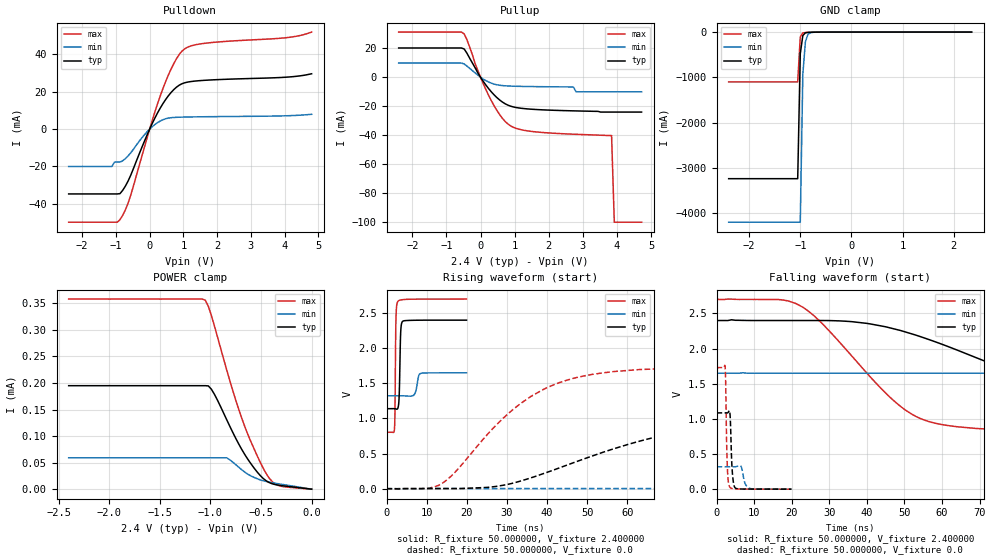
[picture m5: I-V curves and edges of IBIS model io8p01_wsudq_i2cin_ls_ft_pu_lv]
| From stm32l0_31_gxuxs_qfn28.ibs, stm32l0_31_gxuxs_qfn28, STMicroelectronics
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|   Model io8p01_wsudq_i2cin_ls_ft_pu_lv
[Model]  io8p01_wsudq_i2cin_ls_ft_pu_lv
Model_type I/O
Polarity   Non-Inverting
Enable   Active-Low
Vinl =   0.720000V
Vinh =   1.680000V
Vmeas =  1.200000V
Cref =   50.000000pF
Rref =   100.000000M
Vref =   0.0V
C_comp   2.943600pF   2.919700pF   2.965100pF
[Temperature Range]   25.000000   0.105000k   -40.000000
[Pullup Reference]   2.400000V   1.650000V   2.700000V
[Pulldown Reference]   0.0V   0.0V   0.0V
[POWER Clamp Reference]   2.400000V   1.650000V   2.700000V
[GND Clamp Reference]   0.0V   0.0V   0.0V
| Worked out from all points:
|   slope of the pulldown table from 0 to 0.36 V, typ, clamps not added: 28.5 ohm
|   slope of the pullup table from 0 to 0.36 V, typ, clamps not added: 32.2 ohm
|   GND clamp passes 1 mA (typ) near -0.65 V on its own axis
|   rising waveform, R_fixture 50.000000, V_fixture 2.400000: 20-80 % time 285ps typ, 639ps min, 194ps max; typ from 1.14 V to 2.4 V
|   rising waveform, R_fixture 50.000000, V_fixture 0.0: 20-80 % time 39.7ns typ, 107ns min, 19.4ns max; typ from 0.001 V to 1.09 V
|   falling waveform, R_fixture 50.000000, V_fixture 2.400000: 20-80 % time 40.8ns typ, 105ns min, 20.1ns max; typ from 2.4 V to 1.14 V
|   falling waveform, R_fixture 50.000000, V_fixture 0.0: 20-80 % time 483ps typ, 849ps min, 385ps max; typ from 1.09 V to 0.001 V
[Pulldown]
|Voltage   I(typ)   I(min)   I(max)
-2.4V     -34.7mA    -20mA      -49.82mA
-1.12V    -34.7mA    -20mA      -49.82mA
-1.04V    -34.7mA    -17.61mA   -49.82mA
-880mV    -34.55mA   -17.61mA   -48.46mA
-560mV    -24.65mA   -12.68mA   -35.33mA
0V        0A         0A         0A
400mV     13.84mA    5.066mA    22.03mA
720mV     21.25mA    6.254mA    35.26mA
1.04V     24.83mA    6.464mA    43.02mA
1.6V      26.11mA    6.627mA    45.88mA
4V        27.76mA    7.125mA    48.87mA
4.8V      29.63mA    7.94mA     51.96mA
[Pullup]
|Voltage   I(typ)   I(min)   I(max)
-2.4V     20.23mA    9.819mA    31.21mA
-480mV    19.53mA    9.213mA    29.94mA
0V        -580fA     6.14pA     10fA
320mV     -10.16mA   -4.078mA   -16.34mA
640mV     -17.08mA   -5.718mA   -28.28mA
960mV     -20.45mA   -6.129mA   -34.49mA
1.76V     -22.39mA   -6.471mA   -37.97mA
2.72V     -23.16mA   -6.7mA     -39.27mA
2.8V      -23.2mA    -10mA      -39.35mA
3.84V     -24mA      -10mA      -40.2mA
3.92V     -24mA      -10mA      -100mA
4.72V     -24mA      -10mA      -100mA
[GND_clamp]
|Voltage   I(typ)   I(min)   I(max)
-2.4V     -3.237A    -4.198A    -1.1A
-1.05V    -3.237A    -4.198A    -1.1A
-1V       -475.8mA   -4.198A    -104.2mA
-950mV    -76.24mA   -935.4mA   -18.39mA
-900mV    -16.61mA   -212.9mA   -9.105mA
-850mV    -6.547mA   -50.94mA   -6.589mA
-800mV    -3.998mA   -13.81mA   -4.86mA
-650mV    -1.043mA   -1.182mA   -1.146mA
2.35V     0A         0A         0A
[POWER_clamp]
|Voltage   I(typ)   I(min)   I(max)
-2.4V     195uA      59.14uA    358.2uA
-1.05V    195uA      59.14uA    356uA
-1.02V    194.5uA    59.14uA    344.5uA
-960mV    178.7uA    59.14uA    307.4uA
-840mV    131.4uA    59.14uA    225.5uA
-690mV    74.82uA    36.58uA    133.7uA
-600mV    48.08uA    24.92uA    89.53uA
-510mV    26.23uA    17.69uA    51.64uA
-450mV    15.91uA    14.53uA    29.77uA
-390mV    10.19uA    12.23uA    14.39uA
-330mV    7.608uA    10.24uA    6.963uA
0V        0A         0A         0A
[Ramp]
| variable   typ   min   max
dV/dt_r  0.65101/39.64698n   0.19024/0.10645u   1.03799/19.35862n
dV/dt_f  0.75618/40.68925n   0.19440/0.10448u   1.13779/20.06486n
R_load = 50.000000
[Rising Waveform]
R_fixture= 50.000000
V_fixture= 2.400000
V_fixture_min= 1.650000
V_fixture_max= 2.700000
|time   V(typ)   V(min)   V(max)
0s        1.14V      1.323V     803.7mV
1.962ns   1.14V      1.323V     841.1mV
2.082ns   1.139V     1.323V     1.015V
2.362ns   1.135V     1.323V     2.437V
2.803ns   1.144V     1.323V     2.664V
3.163ns   1.337V     1.323V     2.681V
3.524ns   2.216V     1.323V     2.687V
3.924ns   2.376V     1.323V     2.69V
8.609ns   2.399V     1.643V     2.699V
19.94ns   2.4V       1.65V      2.7V
[Rising Waveform]
R_fixture= 50.000000
V_fixture= 0.0
V_fixture_min= 0.0
V_fixture_max= 0.0
|time   V(typ)   V(min)   V(max)
0s        880.8uV    1.332mV    514.1uV
14.01ns   2.449mV    2.469mV    82.21mV
30.03ns   59.96mV    2.471mV    1.053V
40.04ns   234mV      2.471mV    1.439V
49.05ns   421.1mV    2.475mV    1.604V
63.06ns   676.5mV    2.557mV    1.697V
86.09ns   927.7mV    3.733mV    1.727V
125.1ns   1.06V      46.56mV    1.73V
250.2ns   1.086V     265.5mV    1.73V
498.5ns   1.086V     318.6mV    1.73V
[Falling Waveform]
R_fixture= 50.000000
V_fixture= 2.400000
V_fixture_min= 1.650000
V_fixture_max= 2.700000
|time   V(typ)   V(min)   V(max)
0s        2.4V       1.65V      2.7V
21.02ns   2.4V       1.65V      2.643V
28.03ns   2.4V       1.65V      2.362V
50.05ns   2.24V      1.65V      1.134V
57.06ns   2.119V     1.65V      954.1mV
69.07ns   1.872V     1.65V      864.5mV
97.1ns    1.383V     1.65V      816.9mV
138.1ns   1.198V     1.634V     805.4mV
286.3ns   1.14V      1.382V     803.7mV
498.5ns   1.14V      1.323V     803.7mV
[Falling Waveform]
R_fixture= 50.000000
V_fixture= 0.0
V_fixture_min= 0.0
V_fixture_max= 0.0
|time   V(typ)   V(min)   V(max)
0s        1.086V     318.6mV    1.73V
2.282ns   1.086V     318.6mV    1.747V
2.402ns   1.086V     318.6mV    1.595V
2.643ns   1.085V     318.6mV    789.6mV
2.843ns   1.085V     318.6mV    372.1mV
3.483ns   1.112V     318.6mV    33.95mV
4.204ns   242.8mV    318.4mV    8.261mV
4.925ns   20.67mV    318.5mV    4.606mV
8.889ns   1.756mV    10.72mV    1.251mV
19.94ns   880.8uV    1.332mV    514.1uV
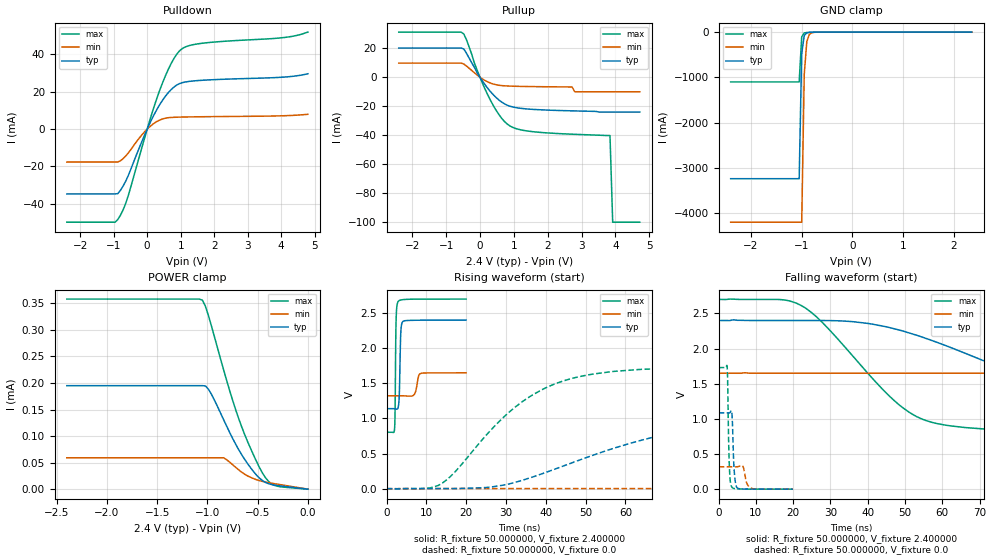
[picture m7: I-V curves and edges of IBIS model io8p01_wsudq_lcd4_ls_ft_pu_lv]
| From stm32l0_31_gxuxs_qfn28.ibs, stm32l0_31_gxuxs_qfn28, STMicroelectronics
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|   Model io8p01_wsudq_lcd4_ls_ft_pu_lv
[Model]  io8p01_wsudq_lcd4_ls_ft_pu_lv
Model_type I/O
Polarity   Non-Inverting
Enable   Active-Low
Vinl =   0.720000V
Vinh =   1.680000V
Vmeas =  1.200000V
Cref =   50.000000pF
Rref =   100.000000M
Vref =   0.0V
C_comp   3.178800pF   3.170000pF   3.206700pF
[Temperature Range]   25.000000   0.105000k   -40.000000
[Pullup Reference]   2.400000V   1.650000V   2.700000V
[Pulldown Reference]   0.0V   0.0V   0.0V
[POWER Clamp Reference]   2.400000V   1.650000V   2.700000V
[GND Clamp Reference]   0.0V   0.0V   0.0V
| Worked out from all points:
|   slope of the pulldown table from 0 to 0.36 V, typ, clamps not added: 28.5 ohm
|   slope of the pullup table from 0 to 0.36 V, typ, clamps not added: 32.2 ohm
|   GND clamp passes 1 mA (typ) near -0.64 V on its own axis
|   rising waveform, R_fixture 50.000000, V_fixture 2.400000: 20-80 % time 296ps typ, 645ps min, 210ps max; typ from 1.14 V to 2.4 V
|   rising waveform, R_fixture 50.000000, V_fixture 0.0: 20-80 % time 39.6ns typ, 107ns min, 19.4ns max; typ from 0.001 V to 1.09 V
|   falling waveform, R_fixture 50.000000, V_fixture 2.400000: 20-80 % time 40.7ns typ, 105ns min, 20.1ns max; typ from 2.4 V to 1.14 V
|   falling waveform, R_fixture 50.000000, V_fixture 0.0: 20-80 % time 491ps typ, 852ps min, 395ps max; typ from 1.09 V to 0.001 V
[Pulldown]
|Voltage   I(typ)   I(min)   I(max)
-2.4V     -34.7mA    -17.6mA    -49.82mA
-960mV    -34.7mA    -17.6mA    -49.82mA
-880mV    -34.55mA   -17.6mA    -48.46mA
-720mV    -30.52mA   -15.8mA    -43.27mA
-560mV    -24.65mA   -12.68mA   -35.33mA
0V        0A         0A         0A
400mV     13.84mA    5.066mA    22.03mA
720mV     21.25mA    6.254mA    35.26mA
1.04V     24.83mA    6.464mA    43.02mA
1.6V      26.11mA    6.627mA    45.88mA
4V        27.76mA    7.125mA    48.87mA
4.8V      29.63mA    7.94mA     51.96mA
[Pullup]
|Voltage   I(typ)   I(min)   I(max)
-2.4V     20.23mA    9.819mA    31.21mA
-480mV    19.53mA    9.213mA    29.94mA
0V        90fA       7.58pA     10fA
320mV     -10.16mA   -4.078mA   -16.34mA
640mV     -17.08mA   -5.718mA   -28.28mA
960mV     -20.45mA   -6.129mA   -34.49mA
1.76V     -22.39mA   -6.471mA   -37.97mA
2.72V     -23.16mA   -6.7mA     -39.27mA
2.8V      -23.2mA    -10mA      -39.35mA
3.84V     -24mA      -10mA      -40.2mA
3.92V     -24mA      -10mA      -100mA
4.72V     -24mA      -10mA      -100mA
[GND_clamp]
|Voltage   I(typ)   I(min)   I(max)
-2.4V     -3.238A    -4.199A    -1.101A
-1.05V    -3.238A    -4.199A    -1.101A
-1V       -476.5mA   -4.199A    -104.7mA
-950mV    -76.68mA   -936.1mA   -18.74mA
-900mV    -16.85mA   -213.2mA   -9.358mA
-850mV    -6.706mA   -51.12mA   -6.778mA
-800mV    -4.108mA   -13.92mA   -4.995mA
-650mV    -1.07mA    -1.211mA   -1.175mA
2.35V     0A         0A         0A
[POWER_clamp]
|Voltage   I(typ)   I(min)   I(max)
-2.4V     195uA      59.14uA    358.2uA
-1.05V    195uA      59.14uA    356uA
-1.02V    194.5uA    59.14uA    344.5uA
-960mV    178.7uA    59.14uA    307.4uA
-840mV    131.4uA    59.14uA    225.5uA
-690mV    74.82uA    36.58uA    133.7uA
-600mV    48.08uA    24.92uA    89.53uA
-510mV    26.23uA    17.69uA    51.64uA
-450mV    15.91uA    14.53uA    29.77uA
-390mV    10.19uA    12.23uA    14.39uA
-330mV    7.608uA    10.25uA    6.963uA
0V        0A         0A         0A
[Ramp]
| variable   typ   min   max
dV/dt_r  0.65095/39.51106n   0.19013/0.10655u   1.03799/19.37129n
dV/dt_f  0.75618/40.65142n   0.19446/0.10508u   1.13779/20.04377n
R_load = 50.000000
[Rising Waveform]
R_fixture= 50.000000
V_fixture= 2.400000
V_fixture_min= 1.650000
V_fixture_max= 2.700000
|time   V(typ)   V(min)   V(max)
0s        1.14V      1.323V     803.7mV
1.962ns   1.14V      1.323V     841.5mV
2.082ns   1.139V     1.323V     1.015V
2.362ns   1.135V     1.323V     2.393V
2.843ns   1.15V      1.323V     2.662V
3.163ns   1.335V     1.323V     2.679V
3.564ns   2.241V     1.323V     2.687V
4.004ns   2.377V     1.323V     2.691V
8.649ns   2.399V     1.642V     2.699V
19.94ns   2.4V       1.65V      2.7V
[Rising Waveform]
R_fixture= 50.000000
V_fixture= 0.0
V_fixture_min= 0.0
V_fixture_max= 0.0
|time   V(typ)   V(min)   V(max)
0s        880.8uV    1.332mV    514.1uV
14.01ns   2.455mV    2.47mV     81.87mV
30.03ns   59.72mV    2.472mV    1.053V
40.04ns   233.6mV    2.472mV    1.438V
49.05ns   420.4mV    2.478mV    1.603V
63.06ns   676.1mV    2.553mV    1.696V
87.09ns   934.2mV    3.859mV    1.727V
122.1ns   1.056V     41.07mV    1.73V
253.3ns   1.086V     268.3mV    1.73V
498.5ns   1.086V     318.6mV    1.73V
[Falling Waveform]
R_fixture= 50.000000
V_fixture= 2.400000
V_fixture_min= 1.650000
V_fixture_max= 2.700000
|time   V(typ)   V(min)   V(max)
0s        2.4V       1.65V      2.7V
21.02ns   2.4V       1.65V      2.643V
27.03ns   2.4V       1.65V      2.413V
51.05ns   2.224V     1.65V      1.097V
58.06ns   2.099V     1.65V      940.1mV
71.07ns   1.828V     1.65V      857.4mV
100.1ns   1.354V     1.65V      814.6mV
137.1ns   1.2V       1.635V     805.5mV
288.3ns   1.14V      1.381V     803.7mV
498.5ns   1.14V      1.323V     803.7mV
[Falling Waveform]
R_fixture= 50.000000
V_fixture= 0.0
V_fixture_min= 0.0
V_fixture_max= 0.0
|time   V(typ)   V(min)   V(max)
0s        1.086V     318.6mV    1.73V
2.282ns   1.086V     318.6mV    1.746V
2.402ns   1.086V     318.6mV    1.594V
2.683ns   1.085V     318.6mV    695.8mV
2.883ns   1.085V     318.6mV    330.1mV
3.524ns   1.1V       318.6mV    33.09mV
4.164ns   277.6mV    318.4mV    9.295mV
4.965ns   20.54mV    318.7mV    4.623mV
8.889ns   1.809mV    10.76mV    1.28mV
19.94ns   880.8uV    1.332mV    514.1uV
